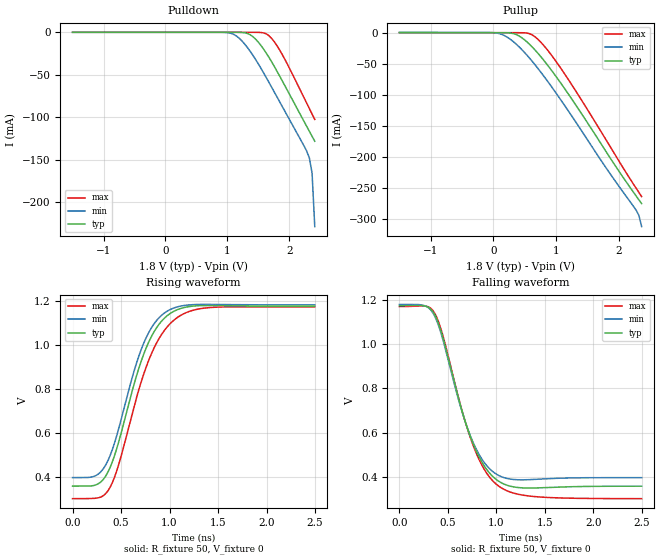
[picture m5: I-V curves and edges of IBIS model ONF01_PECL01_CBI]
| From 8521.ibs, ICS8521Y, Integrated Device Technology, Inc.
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[Model]   ONF01_PECL01_CBI
Model_type   Output_ECL
Polarity   Non-Inverting
|   typ   min   max
C_comp   2pF   1.5pF   2.5pF
Vmeas = 0.764V
Rref = 50
Cref = 0
Vref = 0V
|   typ   min   max
[Voltage range]   1.8V   1.6V   2.0V
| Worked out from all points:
|   rising waveform, R_fixture 50, V_fixture 0: 20-80 % time 334ps typ, 318ps min, 366ps max; typ from 0.357 V to 1.18 V
|   falling waveform, R_fixture 50, V_fixture 0: 20-80 % time 327ps typ, 316ps min, 351ps max; typ from 1.18 V to 0.357 V
[Pulldown]
|Voltage   I (typ)   I (min)   I (max)
|Note, modeling breaks down at 250mA and above.  This is well beyond the functional   |
|operating range of the device.  Should this scenario occur, catastrophic failure and   |
|possible damage to the device and/or board is of higher concern than the I-V curve   |
|behavior.  The IBIS checker will flag currents in excess of 10A with warnings.  Lines   |
|with currents in excess of 0.35 A have been commented out.  The points still remain|
|available to the user if the user desires to use them.   |
-1.5V     4.8pA      -6.998pA   5.052pA
929.8mV   -8.632nA   -74.66uA   -2.272pA
1.148V    -21.11uA   -4.452mA   -16.59pA
1.322V    -1.351mA   -17.8mA    -69nA
1.409V    -4.947mA   -26.8mA    -3.296uA
1.583V    -19.7mA    -47.64mA   -690.8uA
1.714V    -34.74mA   -64.69mA   -7.123mA
1.932V    -63.44mA   -93.56mA   -32.4mA
2.28V     -110.9mA   -140.1mA   -83.46mA
2.324V    -116.7mA   -148.2mA   -89.91mA
2.367V    -122.6mA   -165.9mA   -96.33mA
2.411V    -128.5mA   -229.1mA   -102.7mA
| 2.45448e+00   -1.34319e-01   -4.43619e-01   -1.09090e-01
| 2.49805e+00   -1.40300e-01   -6.94384e-01   -1.15429e-01
| 2.54161e+00   -1.47050e-01   -9.45129e-01   -1.21738e-01
| 2.58517e+00   -1.58083e-01   -1.19591e+00   -1.28016e-01
| 2.62874e+00   -1.92559e-01   -1.44672e+00   -1.34262e-01
| 2.67230e+00   -3.51473e-01   -1.69751e+00   -1.40476e-01
| 2.71586e+00   -6.22918e-01   -1.94828e+00   -1.46658e-01
| 2.75943e+00   -8.94344e-01   -2.19904e+00   -1.52817e-01
| 2.80299e+00   -1.16585e+00   -2.44979e+00   -1.59012e-01
| 2.84655e+00   -1.43734e+00   -2.70052e+00   -1.65773e-01
| 2.89011e+00   -1.70881e+00   -2.95123e+00   -1.77725e-01
| 2.93368e+00   -1.98027e+00   -3.20193e+00   -2.35301e-01
| 2.97724e+00   -2.25171e+00   -3.45262e+00   -5.24468e-01
| 3.02080e+00   -2.52313e+00   -3.70330e+00   -8.70399e-01
| 3.06437e+00   -2.79453e+00   -3.95396e+00   -1.21631e+00
| 3.10793e+00   -3.06592e+00   -4.20462e+00   -1.56219e+00
| 3.15149e+00   -3.33730e+00   -4.45526e+00   -1.90805e+00
| 3.19506e+00   -3.60866e+00   -4.70589e+00   -2.25389e+00
| 3.23862e+00   -3.88000e+00   -4.95651e+00   -2.59970e+00
| 3.28218e+00   -4.15134e+00   -5.20712e+00   -2.94550e+00
| 3.32575e+00   -4.42266e+00   -5.45772e+00   -3.29128e+00
| 3.36931e+00   -4.69396e+00   -5.70831e+00   -3.63704e+00
| 3.41287e+00   -4.96526e+00   -5.95890e+00   -3.98278e+00
| 3.45644e+00   -5.23654e+00   -6.20948e+00   -4.32850e+00
| 3.50000e+00   -5.50782e+00   -6.46005e+00   -4.67420e+00
| 3.51000e+00   -5.57009e+00   -6.51757e+00   -4.75356e+00
| 3.52800e+00   -5.68217e+00   -6.62110e+00   -4.89640e+00
| 3.54600e+00   -5.79425e+00   -6.72463e+00   -5.03923e+00
| 3.56400e+00   -5.90634e+00   -6.82816e+00   -5.18206e+00
| 3.58200e+00   -6.01842e+00   -6.93169e+00   -5.32489e+00
| 3.60000e+00   -6.13049e+00   -7.03521e+00   -5.46772e+00
[Pullup]
|Voltage   I (typ)   I (min)   I (max)
|Note, modeling breaks down at 250mA and above.  This is well beyond the functional   |
|operating range of the device.  Should this scenario occur, catastrophic failure and   |
|possible damage to the device and/or board is of higher concern than the I-V curve   |
|behavior.  The IBIS checker will flag currents in excess of 10A with warnings.  Lines   |
|with currents in excess of 0.35 A have been commented out.  The points still remain|
|available to the user if the user desires to use them.   |
-1.5V     544.1nA    623.7uA    5.178pA
58.51mV   -1.259uA   -683.1uA   -119.7fA
189.2mV   -79.51uA   -5.347mA   -626pA
363.4mV   -2.968mA   -18.33mA   -3.132uA
494.1mV   -11.24mA   -31.5mA    -199.7uA
624.8mV   -23.55mA   -46.67mA   -3.874mA
842.6mV   -49.29mA   -75.01mA   -25.19mA
1.104V    -85.14mA   -112.2mA   -61.33mA
1.801V    -191.7mA   -217.8mA   -172.8mA
2.28V     -262.9mA   -285.8mA   -250.5mA
2.324V    -269.1mA   -294.2mA   -257.2mA
2.367V    -275.1mA   -312.1mA   -263.8mA
| 2.41092e+00   -2.81199e-01   -3.75411e-01   -2.70336e-01
| 2.45448e+00   -2.87235e-01   -5.90110e-01   -2.76828e-01
| 2.49805e+00   -2.93376e-01   -8.41028e-01   -2.83266e-01
| 2.54161e+00   -3.00269e-01   -1.09192e+00   -2.89653e-01
| 2.58517e+00   -3.11432e-01   -1.34284e+00   -2.95990e-01
| 2.62874e+00   -3.46027e-01   -1.59378e+00   -3.02282e-01
| 2.67230e+00   -5.05050e-01   -1.84470e+00   -3.08529e-01
| 2.71586e+00   -7.76596e-01   -2.09561e+00   -3.14735e-01
| 2.75943e+00   -1.04812e+00   -2.34649e+00   -3.20909e-01
| 2.80299e+00   -1.31972e+00   -2.59735e+00   -3.27114e-01
| 2.84655e+00   -1.59130e+00   -2.84820e+00   -3.33880e-01
| 2.89011e+00   -1.86286e+00   -3.09903e+00   -3.45833e-01
| 2.93368e+00   -2.13440e+00   -3.34985e+00   -4.03407e-01
| 2.97724e+00   -2.40592e+00   -3.60066e+00   -6.92574e-01
| 3.02080e+00   -2.67742e+00   -3.85145e+00   -1.03851e+00
| 3.06437e+00   -2.94891e+00   -4.10223e+00   -1.38442e+00
| 3.10793e+00   -3.22038e+00   -4.35300e+00   -1.73031e+00
| 3.15149e+00   -3.49183e+00   -4.60376e+00   -2.07617e+00
| 3.19506e+00   -3.76328e+00   -4.85452e+00   -2.42202e+00
| 3.23862e+00   -4.03471e+00   -5.10526e+00   -2.76785e+00
| 3.28218e+00   -4.30613e+00   -5.35600e+00   -3.11366e+00
| 3.32575e+00   -4.57754e+00   -5.60674e+00   -3.45945e+00
| 3.36931e+00   -4.84894e+00   -5.85747e+00   -3.80523e+00
| 3.41287e+00   -5.12033e+00   -6.10819e+00   -4.15099e+00
| 3.45644e+00   -5.39171e+00   -6.35892e+00   -4.49674e+00
| 3.50000e+00   -5.66309e+00   -6.60964e+00   -4.84248e+00
| 3.51000e+00   -5.72539e+00   -6.66719e+00   -4.92185e+00
| 3.52800e+00   -5.83752e+00   -6.77078e+00   -5.06470e+00
| 3.54600e+00   -5.94964e+00   -6.87438e+00   -5.20755e+00
| 3.56400e+00   -6.06177e+00   -6.97798e+00   -5.35040e+00
| 3.58200e+00   -6.17390e+00   -7.08157e+00   -5.49325e+00
| 3.60000e+00   -6.28602e+00   -7.18517e+00   -5.63610e+00
[Ramp]
|   typ   min   max
dV/dt_r   0.492/0.336n   0.472/0.319n   0.523/0.366n
dV/dt_f   0.496/0.333n   0.477/0.322n   0.524/0.351n
R_load =   50.0000
[Rising Waveform]
R_fixture = 50
V_fixture = 0
V_fixture_max = 0
V_fixture_min = 0
C_fixture = 0.0p
| Time   typ   min   max
0s        357mV      395.7mV    300.1mV
247.7ps   364.1mV    406.9mV    302.6mV
385.4ps   440.2mV    494.2mV    350.6mV
480.5ps   565.3mV    625.9mV    462.2mV
625.6ps   806.5mV    867.1mV    704.4mV
723.2ps   944.3mV    995.6mV    852.5mV
848.3ps   1.065V     1.1V       992.2mV
991ps     1.137V     1.156V     1.088V
1.356ns   1.178V     1.183V     1.166V
2.498ns   1.175V     1.181V     1.172V
[Falling Waveform]
R_fixture = 50
V_fixture = 0
V_fixture_max = 0
V_fixture_min = 0
C_fixture = 0.0p
| Time   typ   min   max
0s        1.176V     1.181V     1.172V
260.3ps   1.174V     1.176V     1.174V
367.9ps   1.131V     1.124V     1.138V
445.4ps   1.036V     1.026V     1.044V
615.6ps   744.3mV    739.4mV    747.8mV
728.2ps   585.4mV    588.7mV    580.9mV
860.9ps   458.4mV    472.7mV    443.7mV
1.004ns   385.6mV    410.5mV    364.1mV
1.379ns   348.6mV    387.3mV    310.3mV
2.498ns   356.8mV    395.5mV    300.2mV
